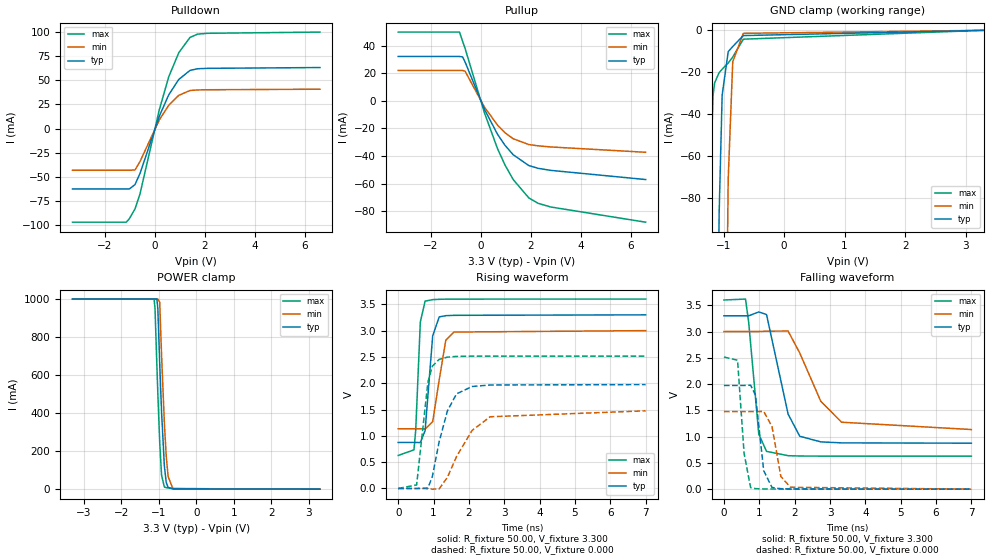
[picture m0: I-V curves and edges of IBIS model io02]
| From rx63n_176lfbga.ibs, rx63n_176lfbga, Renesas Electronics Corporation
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[Model]   io02
Model_type   I/O
Polarity   Non-Inverting
Enable   Active-High
Vinl  =   0.660V
Vinh  =   2.640V
Vmeas =   1.650V
Cref  =   30.00pF
| variable   typ   min   max
C_comp   4.810pF   4.810pF   4.810pF
| variable   typ   min   max
[Temperature Range]   45.000   105.000   -40.000
| variable   typ   min   max
[Voltage Range]   3.300V   3.000V   3.600V
| variable   typ   min   max
[Pullup Reference]   3.300V   3.000V   3.600V
| variable   typ   min   max
[Pulldown Reference]   0.000V   0.000V   0.000V
| variable   typ   min   max
[POWER Clamp Reference] 3.300V   3.000V   3.600V
| variable   typ   min   max
[GND Clamp Reference]   0.000V   0.000V   0.000V
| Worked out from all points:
|   slope of the pulldown table from 0 to 0.495 V, typ, clamps not added: 15.3 ohm
|   slope of the pullup table from 0 to 0.495 V, typ, clamps not added: 26.5 ohm
|   GND clamp passes 1 mA (typ) near -0.60 V on its own axis
|   POWER clamp passes 1 mA (typ) near -0.56 V on its own axis
|   rising waveform, R_fixture 50.00, V_fixture 3.300: 20-80 % time 160ps typ, 229ps min, 107ps max; typ from 0.875 V to 3.3 V
|   rising waveform, R_fixture 50.00, V_fixture 0.000: 20-80 % time 439ps typ, 750ps min, 233ps max; typ from 0 V to 1.97 V
|   falling waveform, R_fixture 50.00, V_fixture 3.300: 20-80 % time 438ps typ, 788ps min, 230ps max; typ from 3.3 V to 0.875 V
|   falling waveform, R_fixture 50.00, V_fixture 0.000: 20-80 % time 184ps typ, 224ps min, 154ps max; typ from 1.97 V to 0 V
[Pulldown]
| io02_strong Pulldown rx631_rx63n
| Thu Mar 22 17:15:49 2012
| voltage   I(typ)   I(min)   I(max)
-3.3V     -62.65mA   -43.27mA   -97.17mA
-1.15V    -62.65mA   -43.27mA   -97.17mA
-1.025V   -62.65mA   -43.27mA   -93.54mA
-800mV    -58.14mA   -42.96mA   -83.35mA
-600mV    -46.61mA   -34.21mA   -67.78mA
175mV     12.96mA    9.063mA    19.79mA
550mV     35.03mA    24.16mA    53.7mA
950mV     50.92mA    34.42mA    78.67mA
1.4V      60.32mA    39.47mA    94.54mA
1.7V      62.04mA    40.07mA    97.97mA
2.1V      62.48mA    40.25mA    98.84mA
6.6V      63.3mA     40.84mA    100.1mA
[Pullup]
| io02_strong Pullup rx631_rx63n
| Thu Mar 22 17:15:49 2012
| voltage   I(typ)   I(min)   I(max)
-3.3V     32.07mA    21.98mA    49.71mA
-850mV    32.07mA    21.98mA    49.71mA
-725mV    31.79mA    21.98mA    43.1mA
-625mV    28.07mA    21.44mA    37.9mA
150mV     -6.167mA   -4.559mA   -8.713mA
675mV     -24.26mA   -17.6mA    -34.7mA
975mV     -32.23mA   -23.07mA   -46.52mA
1.3V      -39mA      -27.43mA   -56.92mA
1.925V    -46.81mA   -31.61mA   -70.21mA
2.3V      -48.81mA   -32.55mA   -74.14mA
2.8V      -50.28mA   -33.35mA   -76.77mA
6.6V      -56.92mA   -37.21mA   -87.76mA
[GND Clamp]
| io02_strong GNDClamp rx631_rx63n
| Thu Mar 22 17:15:49 2012
| voltage   I(typ)   I(min)   I(max)
-3.3V     -1A        -1A        -1A
-1.325V   -1A        -1A        -406.6mA
-1.3V     -983.2mA   -1A        -299.4mA
-1.225V   -615mA     -1A        -75.45mA
-1.175V   -395.1mA   -992.5mA   -30.98mA
-1.15V    -297.6mA   -869.7mA   -25.1mA
-1.075V   -87.49mA   -526mA     -20.19mA
-1.025V   -30.91mA   -328.2mA   -18.56mA
-925mV    -10.2mA    -71.04mA   -15.59mA
-850mV    -7.712mA   -14.99mA   -12.74mA
-675mV    -2.503mA   -1.438mA   -4.223mA
3.3V      0A         0A         0A
[POWER Clamp]
| io02_strong PWRClamp rx631_rx63n
| Thu Mar 22 17:15:49 2012
| voltage   I(typ)   I(min)   I(max)
-3.3V     1A         1A         1A
-1.125V   1A         1A         1A
-1.1V     1A         1A         952.1mA
-1.05V    1A         1A         650.2mA
-1.025V   951.6mA    1A         507.1mA
-975mV    665.2mA    983.6mA    250.2mA
-925mV    406mA      705.8mA    73.52mA
-850mV    120.7mA    345.8mA    11.13mA
-800mV    34.79mA    171.7mA    8.224mA
-750mV    9.544mA    66.61mA    6.556mA
-625mV    2.042mA    3.124mA    2.737mA
3.3V      0A         0A         0A
[Ramp]
dV/dt_r   1.184/438.21p  0.886/749.00p  1.509/232.71p
dV/dt_f   1.455/438.02p  1.119/787.01p  1.783/229.46p
R_load = 50.00ohm
[Rising Waveform]
| io02_strong Rising-High rx631_rx63n
| Thu Mar 22 17:15:49 2012
R_fixture = 50.00
V_fixture = 3.300
V_fixture_min = 3.000
V_fixture_max = 3.600
C_fixture = 0.00pF
| Time   V(typ)   V(min)   V(max)
0s        875mV      1.135V     628mV
445ps     876mV      1.135V     734mV
495ps     875mV      1.135V     1.111V
625ps     873mV      1.135V     3.163V
760ps     1.097V     1.13V      3.561V
975ps     2.901V     1.27V      3.589V
1.16ns    3.261V     2.067V     3.595V
1.345ns   3.284V     2.816V     3.598V
1.575ns   3.291V     2.973V     3.599V
7ns       3.3V       3V         3.6V
[Rising Waveform]
| io02_strong Rising-Low rx631_rx63n
| Thu Mar 22 17:15:49 2012
R_fixture = 50.00
V_fixture = 0.000
C_fixture = 0.00pF
| Time   V(typ)   V(min)   V(max)
0s        0V         0V         0V
520ps     0V         0V         67mV
840ps     9mV        -4mV       2.022V
965ps     227mV      -13mV      2.324V
1.155ns   880mV      -9mV       2.452V
1.39ns    1.472V     210mV      2.496V
1.65ns    1.799V     608mV      2.51V
2.09ns    1.938V     1.104V     2.515V
2.6ns     1.967V     1.363V     2.515V
7ns       1.974V     1.476V     2.515V
[Falling Waveform]
| io02_strong Falling-High rx631_rx63n
| Thu Mar 22 17:15:49 2012
R_fixture = 50.00
V_fixture = 3.300
V_fixture_min = 3.000
V_fixture_max = 3.600
C_fixture = 0.00pF
| Time   V(typ)   V(min)   V(max)
0s        3.3V       3V         3.6V
610ps     3.3V       3V         3.618V
700ps     3.299V     3V         3.177V
985ps     3.373V     3V         1.049V
1.205ns   3.323V     3.007V     719mV
1.815ns   1.429V     3.009V     637mV
2.145ns   1.007V     2.591V     631mV
2.74ns    900mV      1.672V     629mV
3.33ns    881mV      1.274V     628mV
7ns       875mV      1.135V     628mV
[Falling Waveform]
| io02_strong Falling-Low rx631_rx63n
| Thu Mar 22 17:15:49 2012
R_fixture = 50.00
V_fixture = 0.000
C_fixture = 0.00pF
| Time   V(typ)   V(min)   V(max)
0s        1.974V     1.476V     2.515V
385ps     1.974V     1.476V     2.454V
570ps     1.974V     1.476V     683mV
755ps     1.978V     1.476V     29mV
890ps     1.793V     1.476V     10mV
1.125ns   352mV      1.48V      4mV
1.36ns    32mV       1.19V      2mV
1.61ns    9mV        242mV      1mV
1.88ns    4mV        36mV       0V
7ns       0V         0V         0V
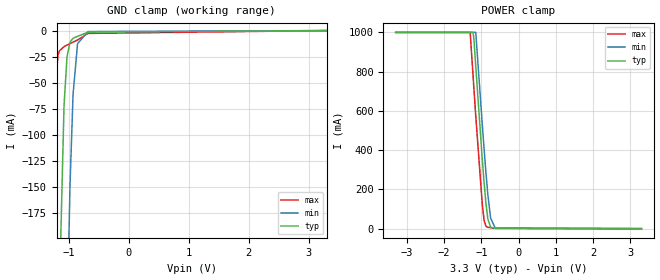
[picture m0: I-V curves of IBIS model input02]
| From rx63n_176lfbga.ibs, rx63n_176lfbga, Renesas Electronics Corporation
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[Model]   input02
Model_type   Input
Vinl  =   0.660V
Vinh  =   2.640V
| variable   typ   min   max
C_comp   4.510pF   4.510pF   4.510pF
| variable   typ   min   max
[Temperature Range]   45.000   105.000   -40.000
| variable   typ   min   max
[Voltage Range]   3.300V   3.000V   3.600V
| variable   typ   min   max
[POWER Clamp Reference] 3.300V   3.000V   3.600V
| variable   typ   min   max
[GND Clamp Reference]   0.000V   0.000V   0.000V
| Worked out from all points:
|   GND clamp passes 1 mA (typ) near -0.64 V on its own axis
|   POWER clamp passes 1 mA (typ) near -0.59 V on its own axis
[GND Clamp]
| input02 GNDClamp rx631_rx63n
| Thu Mar 22 17:15:49 2012
| voltage   I(typ)   I(min)   I(max)
-3.3V     -1A        -1A        -1A
-1.325V   -916.3mA   -1A        -321.5mA
-1.225V   -508.3mA   -1A        -55.89mA
-1.175V   -327mA     -831.7mA   -23.44mA
-1.15V    -246.4mA   -730.5mA   -19.35mA
-1.075V   -71.93mA   -445.9mA   -15.47mA
-1.025V   -24.82mA   -280.5mA   -13.96mA
-975mV    -11.05mA   -147.8mA   -12.54mA
-925mV    -7.426mA   -61.49mA   -11.16mA
-850mV    -5.515mA   -12.55mA   -9.069mA
-675mV    -1.545mA   -924.6uA   -2.718mA
3.3V      0A         0A         0A
[POWER Clamp]
| input02 PWRClamp rx631_rx63n
| Thu Mar 22 17:15:49 2012
| voltage   I(typ)   I(min)   I(max)
-3.3V     1A         1A         1A
-1.3V     1A         1A         1A
-1.225V   1A         1A         787.8mA
-1.2V     968.8mA    1A         716.2mA
-1.15V    826.9mA    1A         574.7mA
-975mV    353.5mA    532.5mA    124.6mA
-925mV    232.2mA    403.8mA    41.28mA
-875mV    126.2mA    282.6mA    11.28mA
-825mV    48.96mA    173.5mA    6.956mA
-750mV    7.191mA    52.97mA    4.872mA
-625mV    1.432mA    2.308mA    1.885mA
3.3V      0A         0A         0A
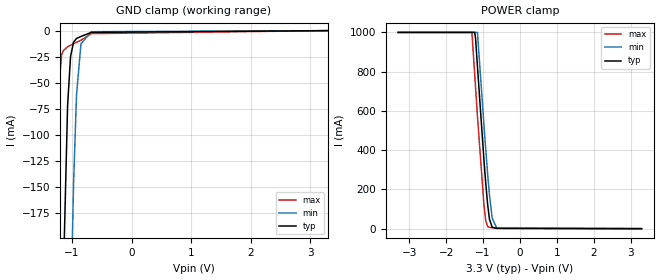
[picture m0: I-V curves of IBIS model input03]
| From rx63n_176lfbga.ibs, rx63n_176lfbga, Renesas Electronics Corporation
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[Model]   input03
Model_type   Input
Vinl  =   0.330V
Vinh  =   2.970V
| variable   typ   min   max
C_comp   4.380pF   4.380pF   4.380pF
| variable   typ   min   max
[Temperature Range]   45.000   105.000   -40.000
| variable   typ   min   max
[Voltage Range]   3.300V   3.000V   3.600V
| variable   typ   min   max
[POWER Clamp Reference] 3.300V   3.000V   3.600V
| variable   typ   min   max
[GND Clamp Reference]   0.000V   0.000V   0.000V
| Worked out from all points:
|   GND clamp passes 1 mA (typ) near -0.64 V on its own axis
|   POWER clamp passes 1 mA (typ) near -0.59 V on its own axis
[GND Clamp]
| input03 GNDClamp rx631_rx63n
| Thu Mar 22 17:15:49 2012
| voltage   I(typ)   I(min)   I(max)
-3.3V     -1A        -1A        -1A
-1.325V   -916mA     -1A        -321.3mA
-1.225V   -508mA     -1A        -55.8mA
-1.175V   -326.9mA   -831.5mA   -23.37mA
-1.15V    -246.3mA   -730.3mA   -19.28mA
-1.075V   -71.86mA   -445.7mA   -15.43mA
-1.025V   -24.78mA   -280.4mA   -13.93mA
-975mV    -11.04mA   -147.8mA   -12.51mA
-925mV    -7.419mA   -61.45mA   -11.15mA
-850mV    -5.518mA   -12.54mA   -9.077mA
-675mV    -1.58mA    -950.5uA   -2.779mA
3.3V      71.14uA    42.63uA    140.5uA
[POWER Clamp]
| input03 PWRClamp rx631_rx63n
| Thu Mar 22 17:15:49 2012
| voltage   I(typ)   I(min)   I(max)
-3.3V     1A         1A         1A
-1.3V     1A         1A         1A
-1.225V   1A         1A         787.5mA
-1.2V     968.5mA    1A         715.9mA
-1.15V    826.6mA    1A         574.4mA
-975mV    353.3mA    532.4mA    124.4mA
-925mV    232mA      403.7mA    41.14mA
-875mV    126mA      282.4mA    11.19mA
-825mV    48.86mA    173.3mA    6.882mA
-750mV    7.141mA    52.88mA    4.818mA
-625mV    1.416mA    2.29mA     1.863mA
3.3V      0A         0A         0A
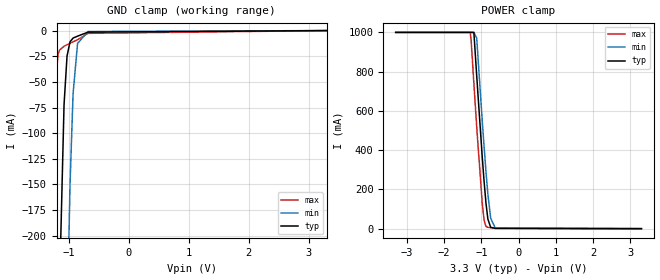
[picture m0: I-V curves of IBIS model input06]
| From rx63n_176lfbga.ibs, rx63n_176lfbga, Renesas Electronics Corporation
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[Model]   input06
Model_type   Input
Vinl  =   0.330V
Vinh  =   2.970V
| variable   typ   min   max
C_comp   5.760pF   5.760pF   5.760pF
| variable   typ   min   max
[Temperature Range]   45.000   105.000   -40.000
| variable   typ   min   max
[Voltage Range]   3.300V   3.000V   3.600V
| variable   typ   min   max
[POWER Clamp Reference] 3.300V   3.000V   3.600V
| variable   typ   min   max
[GND Clamp Reference]   0.000V   0.000V   0.000V
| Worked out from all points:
|   GND clamp passes 1 mA (typ) near -0.64 V on its own axis
|   POWER clamp passes 1 mA (typ) near -0.59 V on its own axis
[GND Clamp]
| input06 GNDClamp rx631_rx63n
| Thu Mar 22 17:15:49 2012
| voltage   I(typ)   I(min)   I(max)
-3.3V     -1A        -1A        -1A
-1.325V   -942.7mA   -1A        -329.1mA
-1.225V   -521.2mA   -1A        -56.06mA
-1.175V   -334.3mA   -854.7mA   -23.2mA
-1.15V    -251.3mA   -750.2mA   -19.09mA
-1.075V   -72.45mA   -456.4mA   -15.24mA
-1.025V   -24.76mA   -286mA     -13.75mA
-975mV    -10.94mA   -149.9mA   -12.35mA
-925mV    -7.326mA   -61.86mA   -10.99mA
-850mV    -5.435mA   -12.5mA    -8.938mA
-675mV    -1.521mA   -910.4uA   -2.678mA
3.3V      0A         0A         0A
[POWER Clamp]
| input06 PWRClamp rx631_rx63n
| Thu Mar 22 17:15:49 2012
| voltage   I(typ)   I(min)   I(max)
-3.3V     1A         1A         1A
-1.3V     1A         1A         1A
-1.275V   1A         1A         962.4mA
-1.2V     999.5mA    1A         738.9mA
-1.125V   780.3mA    971.9mA    520.6mA
-975mV    363.4mA    548.1mA    127.4mA
-925mV    238.1mA    415.1mA    41.69mA
-875mV    128.7mA    289.8mA    11.2mA
-825mV    49.49mA    177.3mA    6.87mA
-750mV    7.147mA    53.54mA    4.809mA
-625mV    1.411mA    2.287mA    1.858mA
3.3V      0A         0A         0A
